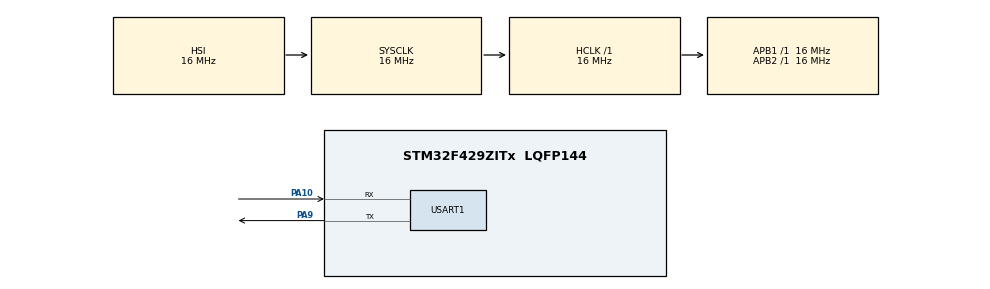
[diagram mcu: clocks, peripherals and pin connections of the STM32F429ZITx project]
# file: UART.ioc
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Mcu.Family=STM32F4
Mcu.Name=STM32F429ZITx
Mcu.Package=LQFP144
NVIC.PriorityGroup=NVIC_PRIORITYGROUP_4
PA10.Mode=Asynchronous
PA10.Signal=USART1_RX
PA9.Mode=Asynchronous
PA9.Signal=USART1_TX
ProjectManager.HeapSize=0x200
ProjectManager.StackSize=0x400
ProjectManager.TargetToolchain=STM32CubeIDE
RCC.AHBFreq_Value=16000000
RCC.APB1Freq_Value=16000000
RCC.APB2Freq_Value=16000000
RCC.CortexFreq_Value=16000000
RCC.HSE_VALUE=25000000
RCC.HSI_VALUE=16000000
RCC.LSE_VALUE=32768
RCC.SYSCLKFreq_VALUE=16000000
RCC.VCOOutputFreq_Value=192000000
USART1.VirtualMode=VM_ASYNC
board=custom

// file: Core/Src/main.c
/* USER CODE BEGIN Header */
/**
  ******************************************************************************
  * @file           : main.c
  * @brief          : Main program body
  ******************************************************************************
  * @attention
  *
  * Copyright (c) 2022 STMicroelectronics.
  * All rights reserved.
  *
  * This software is licensed under terms that can be found in the LICENSE file
  * in the root directory of this software component.
  * If no LICENSE file comes with this software, it is provided AS-IS.
  *
  ******************************************************************************
  */
/* USER CODE END Header */
#include "main.h"
#include "ringbuffer.h"
#include <string.h>
#include <stdio.h>
#include <stdlib.h>
#define WELCOME_MSG "Welcome to the Discovery management console\r\n"
#define MAIN_MENU   "Select the option you are interested in:\r\n\t1. Toggle LD2 LED\r\n\t2. Read USER BUTTON status\r\n\t3. Clear screen and print this message "
#define PROMPT "\r\n> "

UART_HandleTypeDef huart1;
char ReadBuf[1];
__IO ITStatus UartReady = SET;
RingBuffer txBuf, rxBuf;
uint8_t txData;

void printWelcomeMessage(void);
int8_t readUserInput(void);
uint8_t processUserInput(uint8_t opt);
void performCriticalTasks(void);

void SystemClock_Config(void);
static void MX_GPIO_Init(void);
static void MX_USART1_UART_Init(void);

int main(void)
{
	uint8_t opt = 0;

  /* MCU Configuration--------------------------------------------------------*/

  /* Reset of all peripherals, Initializes the Flash interface and the Systick. */
  HAL_Init();

  /* Configure the system clock */
  SystemClock_Config();

  /* Initialize all configured peripherals */
  MX_GPIO_Init();
  MX_USART1_UART_Init();

  /* Enable USART interrupt */
  HAL_NVIC_SetPriority(USART1_IRQn, 0, 0);
  HAL_NVIC_EnableIRQ(USART1_IRQn);

  printWelcomeMessage();

  /* Infinite loop */
  while (1)
  {
	  opt = readUserInput();
	  if (opt > 0)
	  {
		  processUserInput(opt);
		if(opt == 3)
			printWelcomeMessage();
	  }
    performCriticalTasks();
  }
}

uint8_t UART_Transmit(UART_HandleTypeDef *huart, uint8_t *pData, uint16_t len) {
  if(HAL_UART_Transmit_IT(huart, pData, len) != HAL_OK) {
    if(RingBuffer_Write(&txBuf, pData, len) != RING_BUFFER_OK)
      return 0;
  }
  return 1;
}

void performCriticalTasks(void)
{
  HAL_Delay(200);
//  char * msg = "This is task delay every 2s!!!";
//  HAL_UART_Transmit(&huart1, (uint8_t*)msg, strlen(msg), HAL_MAX_DELAY);
}

void USART1_IRQHandler(void)
{
  HAL_UART_IRQHandler(&huart1);
}

void HAL_UART_RxCpltCallback(UART_HandleTypeDef *UartHandle)
{
	UartReady = SET;
}

void HAL_UART_TxCpltCallback(UART_HandleTypeDef *huart) {
  if(RingBuffer_GetDataLength(&txBuf) > 0) {
    RingBuffer_Read(&txBuf, &txData, 1);
    HAL_UART_Transmit_IT(huart, &txData, 1);
  }
}

void printWelcomeMessage(void)
{
  char *strings[] = {"\033[0;0H", "\033[2J", WELCOME_MSG, MAIN_MENU, PROMPT};

  for (uint32_t i = 0; i < 5; i++){
	  UART_Transmit(&huart1, (uint8_t*)strings[i], strlen(strings[i]));

    while (HAL_UART_GetState(&huart1) == HAL_UART_STATE_BUSY_TX ||
    		HAL_UART_GetState(&huart1) == HAL_UART_STATE_BUSY_TX_RX);
  }
}

int8_t readUserInput(void) {
  int8_t retVal = -1;

  if(UartReady == SET) {
    UartReady = RESET;
    HAL_UART_Receive_IT(&huart1, (uint8_t*)ReadBuf, 1);
    retVal = atoi(ReadBuf);
  }
  return retVal;
}

uint8_t processUserInput(uint8_t opt)
{
  char msg[30];

  if (!opt || opt > 3)
  {
    return 0;
  }

  sprintf(msg, "%d", opt);
  UART_Transmit(&huart1, (uint8_t*)msg, strlen(msg));

  switch(opt)
  {
  case 1:
    HAL_GPIO_TogglePin(GPIOG, GPIO_PIN_14);
    break;
  case 2:
    sprintf(msg, "\r\nUSER BUTTON status: %s",
    		HAL_GPIO_ReadPin(GPIOA, GPIO_PIN_0) == GPIO_PIN_SET ? "PRESSED" : "RELEASED");
    UART_Transmit(&huart1, (uint8_t*)msg, strlen(msg));
    while (HAL_UART_GetState(&huart1) == HAL_UART_STATE_BUSY_TX ||
    		HAL_UART_GetState(&huart1) == HAL_UART_STATE_BUSY_TX_RX);
    break;
  case 3:
	  return 2;
  };
  UART_Transmit(&huart1, (uint8_t*)PROMPT, strlen(PROMPT));
  return 1;
}

void SystemClock_Config(void)
{
  RCC_OscInitTypeDef RCC_OscInitStruct = {0};
  RCC_ClkInitTypeDef RCC_ClkInitStruct = {0};

  /** Configure the main internal regulator output voltage
  */
  __HAL_RCC_PWR_CLK_ENABLE();
  __HAL_PWR_VOLTAGESCALING_CONFIG(PWR_REGULATOR_VOLTAGE_SCALE3);

  /** Initializes the RCC Oscillators according to the specified parameters
  * in the RCC_OscInitTypeDef structure.
  */
  RCC_OscInitStruct.OscillatorType = RCC_OSCILLATORTYPE_HSI;
  RCC_OscInitStruct.HSIState = RCC_HSI_ON;
  RCC_OscInitStruct.HSICalibrationValue = RCC_HSICALIBRATION_DEFAULT;
  RCC_OscInitStruct.PLL.PLLState = RCC_PLL_NONE;
  if (HAL_RCC_OscConfig(&RCC_OscInitStruct) != HAL_OK)
  {
    Error_Handler();
  }

  /** Initializes the CPU, AHB and APB buses clocks
  */
  RCC_ClkInitStruct.ClockType = RCC_CLOCKTYPE_HCLK|RCC_CLOCKTYPE_SYSCLK
                              |RCC_CLOCKTYPE_PCLK1|RCC_CLOCKTYPE_PCLK2;
  RCC_ClkInitStruct.SYSCLKSource = RCC_SYSCLKSOURCE_HSI;
  RCC_ClkInitStruct.AHBCLKDivider = RCC_SYSCLK_DIV1;
  RCC_ClkInitStruct.APB1CLKDivider = RCC_HCLK_DIV1;
  RCC_ClkInitStruct.APB2CLKDivider = RCC_HCLK_DIV1;

  if (HAL_RCC_ClockConfig(&RCC_ClkInitStruct, FLASH_LATENCY_0) != HAL_OK)
  {
    Error_Handler();
  }
}

static void MX_USART1_UART_Init(void)
{

  huart1.Instance = USART1;
  huart1.Init.BaudRate = 115200;
  huart1.Init.WordLength = UART_WORDLENGTH_8B;
  huart1.Init.StopBits = UART_STOPBITS_1;
  huart1.Init.Parity = UART_PARITY_NONE;
  huart1.Init.Mode = UART_MODE_TX_RX;
  huart1.Init.HwFlowCtl = UART_HWCONTROL_NONE;
  huart1.Init.OverSampling = UART_OVERSAMPLING_16;
  if (HAL_UART_Init(&huart1) != HAL_OK)
  {
    Error_Handler();
  }

}

static void MX_GPIO_Init(void)
{
	GPIO_InitTypeDef GPIO_InitStruct = {0};

  /* GPIO Ports Clock Enable */
  __HAL_RCC_GPIOA_CLK_ENABLE();
  __HAL_RCC_GPIOG_CLK_ENABLE();

  HAL_GPIO_WritePin(GPIOG, GPIO_PIN_14, GPIO_PIN_RESET);

  /* Config Button */
  GPIO_InitStruct.Pin = GPIO_PIN_0;
  GPIO_InitStruct.Mode = GPIO_MODE_IT_FALLING;
  GPIO_InitStruct.Pull = GPIO_NOPULL;
  HAL_GPIO_Init(GPIOA, &GPIO_InitStruct);

  /* Cofig LED */
  GPIO_InitStruct.Pin = GPIO_PIN_14;
  GPIO_InitStruct.Mode = GPIO_MODE_OUTPUT_PP;
  GPIO_InitStruct.Pull = GPIO_NOPULL;
  GPIO_InitStruct.Speed = GPIO_SPEED_LOW;
  HAL_GPIO_Init(GPIOG, &GPIO_InitStruct);

}

void Error_Handler(void)
{
  __disable_irq();
  while (1)
  {
  }
}
